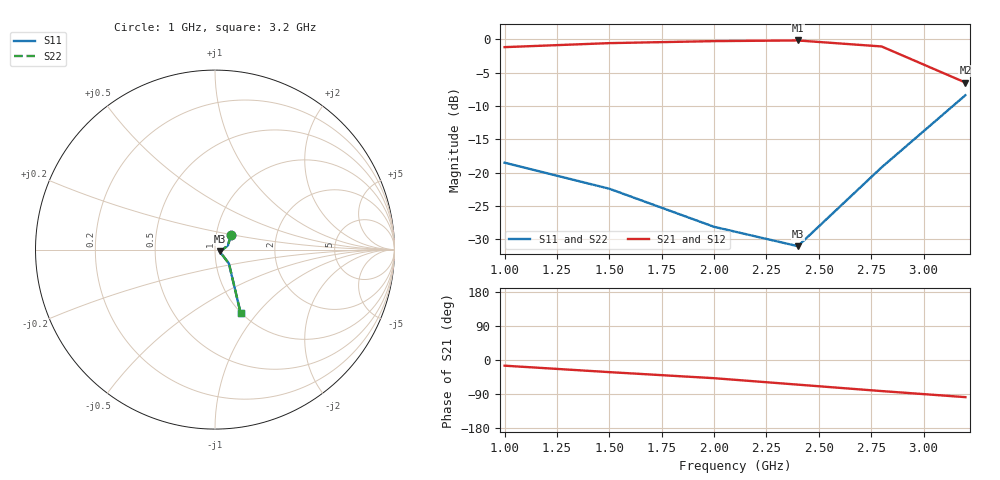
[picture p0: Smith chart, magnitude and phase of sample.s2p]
! Explorer2 RF Bandpass Filter S-Parameters
# GHz S DB R 50
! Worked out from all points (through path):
!   6 points, 1 GHz to 3.2 GHz, reference 50 ohm
!   highest |S21| = -0.20 dB at 2.4 GHz (marker M1); lowest = -6.5 dB at 3.2 GHz (marker M2)
!   lowest |S11| = -31.0 dB at 2.4 GHz (marker M3), VSWR 1.06, Z = 52.7 - j1.11 ohm
!   |S11| at or under -10 dB: start of sweep to 3.141 GHz
!   |S22| runs from -31.0 to -8.4 dB; largest |S21 - S12| = 0
1  -18.50 42.0  -1.20 -15.0  -1.20 -15.0  -18.50 42.0
1.5  -22.40 18.0  -0.60 -32.0  -0.60 -32.0  -22.40 18.0
2  -28.10 -4.0  -0.30 -48.0  -0.30 -48.0  -28.10 -4.0
2.4  -31.00 -22.0  -0.20 -65.0  -0.20 -65.0  -31.00 -22.0
2.8  -19.20 -45.0  -1.10 -82.0  -1.10 -82.0  -19.20 -45.0
3.2  -8.40 -68.0  -6.50 -98.0  -6.50 -98.0  -8.40 -68.0
